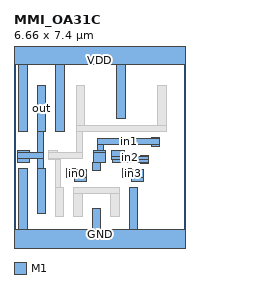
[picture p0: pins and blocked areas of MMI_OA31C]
MACRO MMI_OA31C
	CLASS CORE ;
	FOREIGN MMI_OA31C 0 0 ;
	SIZE 6.66 BY 7.4 ;
	SYMMETRY X Y ;
	SITE CORE1 ;
	PIN out
		DIRECTION output ;
		USE SIGNAL ;
		PORT
			LAYER M1 ;
			RECT 0.9 4.32 1.24 6.08 ;
			LAYER M1 ;
			RECT 0.145 3.495 0.595 3.555 ;
			LAYER M1 ;
			RECT 0.9 3.495 1.13 4.32 ;
			LAYER M1 ;
			RECT 0.145 3.265 1.13 3.495 ;
			LAYER M1 ;
			RECT 0.145 3.105 0.595 3.265 ;
			LAYER M1 ;
			RECT 0.9 2.86 1.13 3.265 ;
			LAYER M1 ;
			RECT 0.9 1.1 1.24 2.86 ;
		END
		AntennaDiffArea 1.8768 ;
	END out
	PIN in1
		DIRECTION input ;
		USE SIGNAL ;
		PORT
			LAYER M1 ;
			RECT 5.34 4.015 5.68 4.065 ;
			LAYER M1 ;
			RECT 3.245 3.785 5.68 4.015 ;
			LAYER M1 ;
			RECT 3.245 3.555 3.475 3.785 ;
			LAYER M1 ;
			RECT 5.34 3.725 5.68 3.785 ;
			LAYER M1 ;
			RECT 3.105 3.495 3.555 3.555 ;
			LAYER M1 ;
			RECT 3.1 3.115 3.555 3.495 ;
			LAYER M1 ;
			RECT 3.045 3.105 3.555 3.115 ;
			LAYER M1 ;
			RECT 3.045 2.775 3.385 3.105 ;
		END
		AntennaGateArea 0.8928 ;
	END in1
	PIN GND
		DIRECTION inout ;
		USE GROUND ;
		PORT
			LAYER M1 ;
			RECT 0.18 0.5 0.52 2.86 ;
			LAYER M1 ;
			RECT 3.04 0.5 3.38 1.315 ;
			LAYER M1 ;
			RECT 4.48 0.5 4.82 2.135 ;
			LAYER M1 ;
			RECT 0 -0.5 6.66 0.5 ;
		END
	END GND
	PIN in2
		DIRECTION input ;
		USE SIGNAL ;
		PORT
			LAYER M1 ;
			RECT 3.845 3.55 4.295 3.555 ;
			LAYER M1 ;
			RECT 3.785 3.335 4.295 3.55 ;
			LAYER M1 ;
			RECT 4.91 3.335 5.25 3.385 ;
			LAYER M1 ;
			RECT 3.785 3.21 5.25 3.335 ;
			LAYER M1 ;
			RECT 3.845 3.105 5.25 3.21 ;
			LAYER M1 ;
			RECT 4.91 3.045 5.25 3.105 ;
		END
		AntennaGateArea 0.8928 ;
	END in2
	PIN VDD
		DIRECTION inout ;
		USE POWER ;
		PORT
			LAYER M1 ;
			RECT 0 6.9 6.66 7.9 ;
			LAYER M1 ;
			RECT 0.18 4.32 0.52 6.9 ;
			LAYER M1 ;
			RECT 1.62 4.32 1.96 6.9 ;
			LAYER M1 ;
			RECT 4 4.8 4.34 6.9 ;
		END
	END VDD
	PIN in3
		DIRECTION input ;
		USE SIGNAL ;
		PORT
			LAYER M1 ;
			RECT 4.24 2.815 4.58 2.86 ;
			LAYER M1 ;
			RECT 4.24 2.52 5.035 2.815 ;
			LAYER M1 ;
			RECT 4.585 2.365 5.035 2.52 ;
		END
		AntennaGateArea 0.8928 ;
	END in3
	PIN in0
		DIRECTION input ;
		USE SIGNAL ;
		PORT
			LAYER M1 ;
			RECT 2.06 2.815 2.4 2.86 ;
			LAYER M1 ;
			RECT 2.06 2.52 2.815 2.815 ;
			LAYER M1 ;
			RECT 2.365 2.365 2.815 2.52 ;
		END
		AntennaGateArea 0.4464 ;
	END in0
	OBS
		LAYER M1 ;
		RECT 2.42 4.53 2.76 6.08 ;
		LAYER M1 ;
		RECT 5.58 4.53 5.92 6.08 ;
		LAYER M1 ;
		RECT 2.42 4.3 5.92 4.53 ;
		LAYER M1 ;
		RECT 1.36 3.495 1.7 3.55 ;
		LAYER M1 ;
		RECT 2.42 3.495 2.65 4.3 ;
		LAYER M1 ;
		RECT 1.36 3.265 2.65 3.495 ;
		LAYER M1 ;
		RECT 1.36 3.21 1.83 3.265 ;
		LAYER M1 ;
		RECT 1.6 2.135 1.83 3.21 ;
		LAYER M1 ;
		RECT 1.6 0.975 1.94 2.135 ;
		LAYER M1 ;
		RECT 2.32 1.905 4.1 2.135 ;
		LAYER M1 ;
		RECT 2.32 0.975 2.66 1.905 ;
		LAYER M1 ;
		RECT 3.76 0.975 4.1 1.905 ;
	END
END MMI_OA31C
